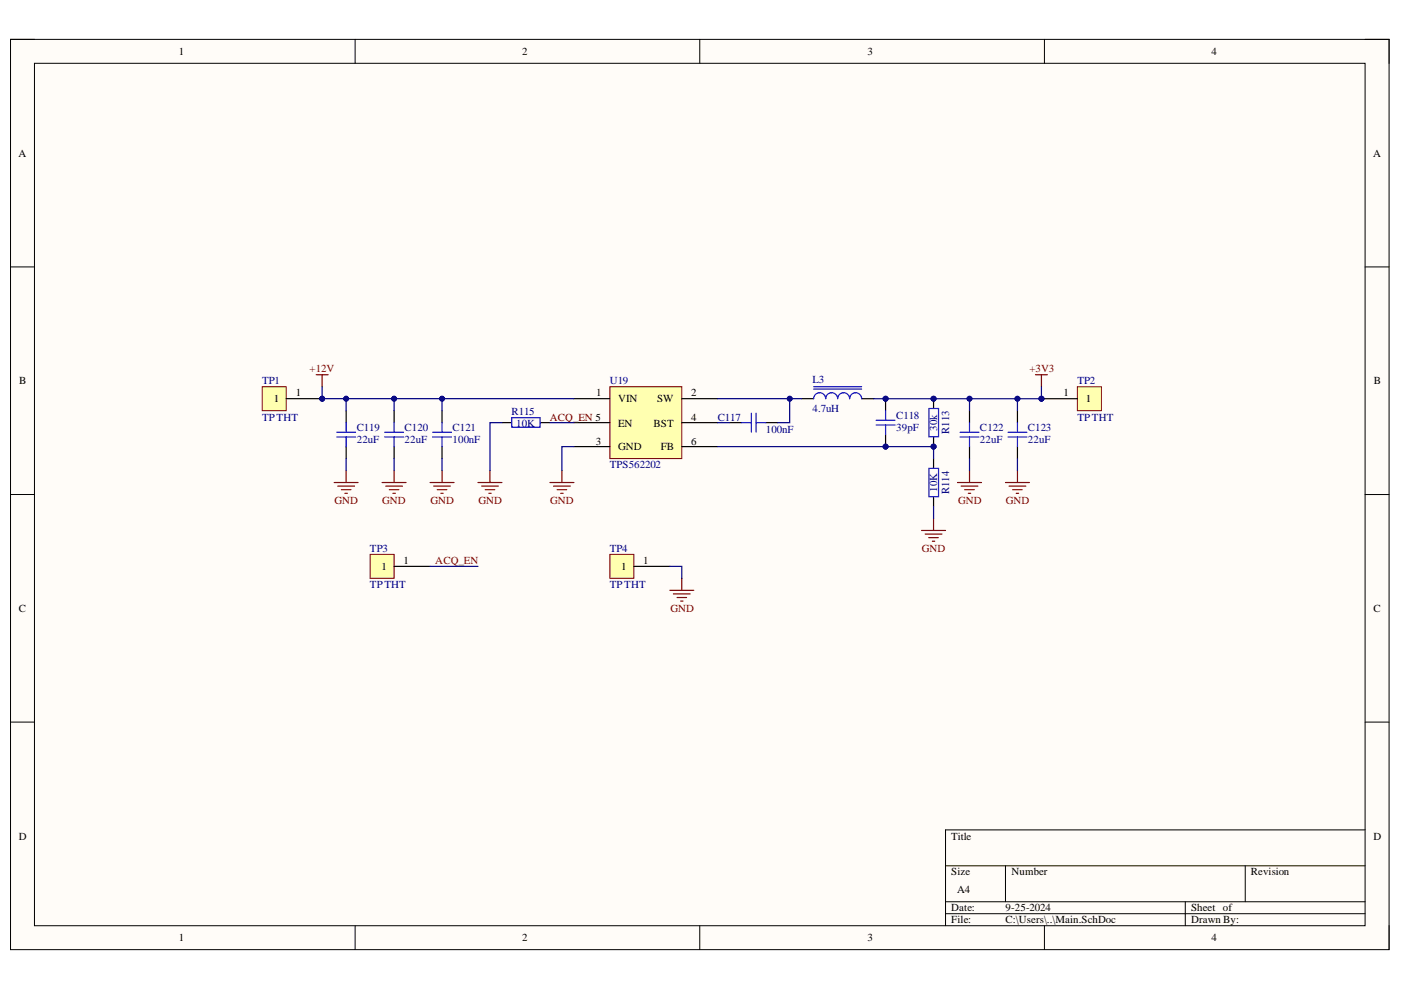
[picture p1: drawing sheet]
<svg xmlns="http://www.w3.org/2000/svg" width="297mm" height="210mm" viewBox="0 0 297 210" stroke-linecap="round" stroke-linejoin="round" font-family="sans-serif">
<defs><g id="words">
<g font-size="2.3">
<text x="37.9" y="11.7">1</text>
<text x="110.7" y="11.7">2</text>
<text x="183.9" y="11.7">3</text>
<text x="256.8" y="11.7">4</text>
<text x="3.9" y="33.3">A</text>
<text x="291.1" y="33.3">A</text>
<text x="4.1" y="81.5">B</text>
<text x="291.3" y="81.5">B</text>
<text x="58" y="85.3">1</text>
<text x="62.7" y="84">1</text>
<text x="126.4" y="84">1</text>
<text x="131" y="85.3">VIN</text>
<text x="139.3" y="85.3">SW</text>
<text x="146.5" y="84">2</text>
<text x="146.5" y="89.2">4</text>
<text x="225.5" y="84">1</text>
<text x="230.2" y="85.3">1</text>
<text x="126.3" y="94.2">3</text>
<text x="131" y="95.5">GND</text>
<text x="131" y="90.4">EN</text>
<text x="138.6" y="90.4">BST</text>
<text x="140.1" y="95.5">FB</text>
<text x="146.5" y="94.2">6</text>
<text x="85.5" y="119.6">1</text>
<text x="136.4" y="119.6">1</text>
<text x="80.9" y="120.9">1</text>
<text x="131.7" y="120.9">1</text>
<text x="4" y="129.7">C</text>
<text x="291.2" y="129.7">C</text>
<text x="4" y="178">D</text>
<text x="201.7" y="178">Title</text>
<text x="291.2" y="178">D</text>
<text x="201.7" y="185.6">Size</text>
<text x="214.5" y="185.6">Number</text>
<text x="265.2" y="185.6">Revision</text>
<text x="203" y="189.4">A4</text>
<text x="201.7" y="193.2">Date:</text>
<text x="201.7" y="195.8">File:</text>
<text x="213.2" y="193.2">9-25-2024</text>
<text x="213.2" y="195.8">C:\Users\..\Main.SchDoc</text>
<text x="252.5" y="193.2">Sheet of</text>
<text x="252.5" y="195.8">Drawn By:</text>
<text x="37.9" y="199.6">1</text>
<text x="110.7" y="199.6">2</text>
<text x="183.9" y="199.6">3</text>
<text x="256.8" y="199.6">4</text>
</g>
<g font-size="2.3" fill="#000080">
<text x="55.6" y="81.5">TP1</text>
<text x="129.3" y="81.5">U19</text>
<text x="172.2" y="81.2">L3</text>
<text x="228.4" y="81.5">TP2</text>
<text x="55.6" y="89.2">TPTHT</text>
<text x="108.5" y="88.1">R115</text>
<text x="152.2" y="89.2">C117</text>
<text x="172.2" y="87.3">4.7uH</text>
<text x="190" y="88.9">C118</text>
<text x="228.4" y="89.2">TPTHT</text>
<text x="75.6" y="91.5">C119</text>
<text x="75.6" y="94">22uF</text>
<text x="85.8" y="91.5">C120</text>
<text x="85.8" y="94">22uF</text>
<text x="95.9" y="91.5">C121</text>
<text x="95.9" y="94">100nF</text>
<text x="109.5" y="90.4">10K</text>
<text x="162.3" y="91.7">100nF</text>
<text x="190" y="91.5">39pF</text>
<text x="198.7" y="91.4" transform="rotate(-90 198.7 91.4)">30k</text>
<text x="201.3" y="92" transform="rotate(-90 201.3 92)">R113</text>
<text x="207.8" y="91.5">C122</text>
<text x="207.8" y="94">22uF</text>
<text x="217.9" y="91.5">C123</text>
<text x="217.9" y="94">22uF</text>
<text x="129.3" y="99.3">TPS562202</text>
<text x="198.7" y="104.3" transform="rotate(-90 198.7 104.3)">10K</text>
<text x="201.3" y="104.7" transform="rotate(-90 201.3 104.7)">R114</text>
<text x="78.4" y="117.1">TP3</text>
<text x="129.3" y="117.1">TP4</text>
<text x="78.4" y="124.7">TPTHT</text>
<text x="129.3" y="124.7">TPTHT</text>
</g>
<g font-size="2.3" fill="#800000">
<text x="65.6" y="78.9">+12V</text>
<text x="218.3" y="78.9">+3V3</text>
<text x="116.6" y="89.2">ACQ_EN 5</text>
<text x="70.9" y="106.9">GND</text>
<text x="81" y="106.9">GND</text>
<text x="91.3" y="106.9">GND</text>
<text x="101.4" y="106.9">GND</text>
<text x="116.7" y="106.9">GND</text>
<text x="203.1" y="106.9">GND</text>
<text x="213.3" y="106.9">GND</text>
<text x="92.3" y="119.6">ACQ_EN</text>
<text x="195.4" y="117.1">GND</text>
<text x="142.1" y="129.7">GND</text>
</g>
</g></defs>
<path d="M2.2 8.3h292.3v193h-292.3z" fill-rule="evenodd" fill="#fffcf8"/>
<path d="M2.2 8.3h292.3v193h-292.3z" fill="none" stroke="#000" stroke-width=".21"/>
<path d="M7.3 13.4h282.1v182.9h-282.1z" fill-rule="evenodd" fill="#fffcf8"/>
<g fill="none" stroke="#000" stroke-width=".21">
<path d="M2.2 8.3h5.1M7.3 13.4h282.1v182.9h-282.1zM75.3 8.3v5.1M148.4 8.3v5.1M221.4 8.3v5.1M289.4 8.3h5.1v5.1M2.2 56.6h5.1M289.4 56.6h5.1M2.2 104.8h5.1M289.4 104.9h5.1M2.2 153.1h5.1M289.4 153.1h5.1"/>
<path d="M289.4 176h-88.9v20.3M75.3 196.3v5M148.4 196.3v5M200.5 183.6h88.9M200.5 191.2h88.9M200.5 193.7h88.9M213.2 183.6v7.6M221.4 196.3v5M251.3 191.2v5.1M264 183.6v7.6M294.5 196.3v5"/>
</g>
<path d="M129.3 82h15.3v15.2h-15.3z" fill-rule="evenodd" fill="#ffffb0"/>
<path d="M129.3 82h15.3v15.2h-15.3z" fill="none" stroke="#800000" stroke-width=".21"/>
<path d="M93.7 87.1v2.5M93.7 94.7v2.5M121.7 84.5h7.6M121.7 94.7h7.6M121.7 89.6h7.6M144.6 84.5h7.6M144.6 94.7h7.6M144.6 89.6h7.6M154.7 89.6h2.6M162.3 89.6h2.6M197.9 97.2v2M197.9 105.4v2" fill="none" stroke="#000" stroke-width=".25"/>
<path d="M91.7 91.7h4M91.7 92.6h4M93.7 89.6v2.1M93.7 92.6v2.1M157.3 89.6h2M159.3 87.6v4M160.3 89.6h2M160.3 87.6v4M196.9 99.3h2.1v6h-2.1z" fill="none" stroke="#00f" stroke-width=".25"/>
<g fill="none" stroke="#800000" stroke-width=".25">
<path d="M93.7 99.8v2.5M119.1 99.8v2.5M91.2 102.3h5.1M91.9 103.1h3.6M92.7 103.8h2M93.5 104.6h.5M116.6 102.3h5.1M117.4 103.1h3.5M118.1 103.8h2.1M118.9 104.6h.5M195.4 112.5h5.1M196.2 113.2h3.5"/>
<path d="M196.9 114h2M197.7 114.8h.5M197.9 109.9v2.6"/>
</g>
<circle cx="187.8" cy="94.7" r=".51" fill="#000080"/>
<circle cx="187.8" cy="94.7" r=".51" fill="none" stroke="#000080" stroke-width=".21"/>
<circle cx="187.8" cy="84.5" r=".51" fill="#000080"/>
<circle cx="187.8" cy="84.5" r=".51" fill="none" stroke="#000080" stroke-width=".21"/>
<path d="M187.8 92.2v2.5" fill="none" stroke="#000" stroke-width=".25"/>
<circle cx="187.8" cy="94.7" r=".51" fill="#000080"/>
<circle cx="187.8" cy="94.7" r=".51" fill="none" stroke="#000080" stroke-width=".21"/>
<path d="M187.8 84.5v2.6" fill="none" stroke="#000" stroke-width=".25"/>
<circle cx="187.8" cy="84.5" r=".51" fill="#000080"/>
<circle cx="187.8" cy="84.5" r=".51" fill="none" stroke="#000080" stroke-width=".21"/>
<g fill="none" stroke="#00f" stroke-width=".25">
<path d="M71.4 92.6h4M71.4 91.7h4M73.4 89.6v2.1M73.4 92.6v2.1M81.6 92.6h4M81.6 91.7h4M83.6 89.6v2.1M83.6 92.6v2.1M185.8 90.1h4M185.8 89.1h4M187.8 87.1v2M187.8 90.1v2.1"/>
<path d="M203.6 92.6h4M203.6 91.7h4M205.6 89.6v2.1M205.6 92.6v2.1M213.7 92.6h4M213.7 91.7h4M215.7 89.6v2.1M215.7 92.6v2.1"/>
</g>
<path d="M73.4 87.1v2.5M73.4 94.7v2.5M83.6 87.1v2.5M83.6 94.7v2.5M205.6 87.1v2.5M205.6 94.7v2.5M215.7 87.1v2.5M215.7 94.7v2.5" fill="none" stroke="#000" stroke-width=".25"/>
<g fill="none" stroke="#800000" stroke-width=".25">
<path d="M67 79.5h2.6M68.3 79.5v2.5M219.5 79.5h2.6M220.8 79.5v2.5M73.4 99.8v2.5M83.6 99.8v2.5M205.6 99.8v2.5M215.7 99.8v2.5M70.8 102.3h5.1M71.6 103.1h3.6M72.4 103.8h2M73.1 104.6h.5"/>
<path d="M81 102.3h5.1M81.8 103.1h3.5M82.5 103.8h2.1M83.3 104.6h.5M203 102.3h5.1M203.8 103.1h3.5M204.5 103.8h2.1M205.3 104.6h.5M213.2 102.3h5.1M213.9 103.1h3.6M214.7 103.8h2M215.5 104.6h.5"/>
</g>
<circle cx="197.9" cy="84.5" r=".51" fill="#000080"/>
<circle cx="197.9" cy="84.5" r=".51" fill="none" stroke="#000080" stroke-width=".21"/>
<circle cx="197.9" cy="94.7" r=".51" fill="#000080"/>
<circle cx="197.9" cy="94.7" r=".51" fill="none" stroke="#000080" stroke-width=".21"/>
<path d="M197.9 84.5v2" fill="none" stroke="#000" stroke-width=".25"/>
<circle cx="197.9" cy="84.5" r=".51" fill="#000080"/>
<circle cx="197.9" cy="84.5" r=".51" fill="none" stroke="#000080" stroke-width=".21"/>
<path d="M197.9 92.7v2" fill="none" stroke="#000" stroke-width=".25"/>
<circle cx="197.9" cy="94.7" r=".51" fill="#000080"/>
<circle cx="197.9" cy="94.7" r=".51" fill="none" stroke="#000080" stroke-width=".21"/>
<path d="M108.5 88.6h6v2h-6zM172.5 84.5a1.27 1.27 0 0 1 1.3-1.2 1.27 1.27 0 0 1 1.3 1.2 1.27 1.27 0 0 1 1.2-1.2 1.27 1.27 0 0 1 1.3 1.2 1.27 1.27 0 0 1 1.3-1.2 1.27 1.27 0 0 1 1.2 1.2 1.27 1.27 0 0 1 1.3-1.2 1.27 1.27 0 0 1 1.3 1.2M172.5 82.5h10.2M172.5 82h10.2M196.9 86.6h2.1v6h-2.1z" fill="none" stroke="#00f" stroke-width=".25"/>
<path d="M106.4 89.6h2M114.6 89.6h2M170 84.5h2.5M182.7 84.5h2.5" fill="none" stroke="#000" stroke-width=".25"/>
<path d="M103.9 99.8v2.5M101.3 102.3h5.1M102.1 103.1h3.6M102.9 103.8h2M103.6 104.6h.5" fill="none" stroke="#800000" stroke-width=".25"/>
<circle cx="68.3" cy="84.5" r=".51" fill="#000080"/>
<circle cx="68.3" cy="84.5" r=".51" fill="none" stroke="#000080" stroke-width=".21"/>
<path d="M55.6 82h5.1v5.1h-5.1z" fill-rule="evenodd" fill="#ffffb0"/>
<path d="M55.6 82h5.1v5.1h-5.1z" fill="none" stroke="#800000" stroke-width=".21"/>
<path d="M60.7 84.5h7.6" fill="none" stroke="#000" stroke-width=".25"/>
<circle cx="68.3" cy="84.5" r=".51" fill="#000080"/>
<circle cx="68.3" cy="84.5" r=".51" fill="none" stroke="#000080" stroke-width=".21"/>
<circle cx="220.8" cy="84.5" r=".51" fill="#000080"/>
<circle cx="220.8" cy="84.5" r=".51" fill="none" stroke="#000080" stroke-width=".21"/>
<path d="M228.4 82h5.1v5.1h-5.1z" fill-rule="evenodd" fill="#ffffb0"/>
<path d="M228.4 82h5.1v5.1h-5.1z" fill="none" stroke="#800000" stroke-width=".21"/>
<path d="M220.8 84.5h7.6" fill="none" stroke="#000" stroke-width=".25"/>
<circle cx="220.8" cy="84.5" r=".51" fill="#000080"/>
<circle cx="220.8" cy="84.5" r=".51" fill="none" stroke="#000080" stroke-width=".21"/>
<path d="M78.5 117.5h5.1v5.1h-5.1z" fill-rule="evenodd" fill="#ffffb0"/>
<path d="M78.5 117.5h5.1v5.1h-5.1z" fill="none" stroke="#800000" stroke-width=".21"/>
<path d="M83.6 120.1h7.6" fill="none" stroke="#000" stroke-width=".25"/>
<path d="M152.2 84.5h15.2v5.1h-2.5M152.2 89.6h2.5" fill="none" stroke="#000080" stroke-width=".25"/>
<circle cx="167.4" cy="84.5" r=".51" fill="#000080"/>
<circle cx="167.4" cy="84.5" r=".51" fill="none" stroke="#000080" stroke-width=".21"/>
<path d="M152.2 94.7h45.7v2.5M197.9 107.4v2.5" fill="none" stroke="#000080" stroke-width=".25"/>
<circle cx="197.9" cy="94.7" r=".51" fill="#000080"/>
<circle cx="197.9" cy="94.7" r=".51" fill="none" stroke="#000080" stroke-width=".21"/>
<circle cx="187.8" cy="94.7" r=".51" fill="#000080"/>
<circle cx="187.8" cy="94.7" r=".51" fill="none" stroke="#000080" stroke-width=".21"/>
<path d="M73.4 97.2v2.6M83.6 97.2v2.6M93.7 97.2v2.6M121.7 94.7h-2.6v5.1M167.4 84.5h2.6M205.6 97.2v2.6M215.7 97.2v2.6" fill="none" stroke="#000080" stroke-width=".25"/>
<circle cx="167.4" cy="84.5" r=".51" fill="#000080"/>
<circle cx="167.4" cy="84.5" r=".51" fill="none" stroke="#000080" stroke-width=".21"/>
<path d="M93.7 84.5v2.6" fill="none" stroke="#000080" stroke-width=".25"/>
<circle cx="93.7" cy="84.5" r=".51" fill="#000080"/>
<circle cx="93.7" cy="84.5" r=".51" fill="none" stroke="#000080" stroke-width=".21"/>
<path d="M83.6 84.5v2.6" fill="none" stroke="#000080" stroke-width=".25"/>
<circle cx="83.6" cy="84.5" r=".51" fill="#000080"/>
<circle cx="83.6" cy="84.5" r=".51" fill="none" stroke="#000080" stroke-width=".21"/>
<path d="M73.4 84.5v2.6" fill="none" stroke="#000080" stroke-width=".25"/>
<circle cx="73.4" cy="84.5" r=".51" fill="#000080"/>
<circle cx="73.4" cy="84.5" r=".51" fill="none" stroke="#000080" stroke-width=".21"/>
<path d="M205.6 84.5v2.6" fill="none" stroke="#000080" stroke-width=".25"/>
<circle cx="205.6" cy="84.5" r=".51" fill="#000080"/>
<circle cx="205.6" cy="84.5" r=".51" fill="none" stroke="#000080" stroke-width=".21"/>
<path d="M215.7 84.5v2.6" fill="none" stroke="#000080" stroke-width=".25"/>
<circle cx="215.7" cy="84.5" r=".51" fill="#000080"/>
<circle cx="215.7" cy="84.5" r=".51" fill="none" stroke="#000080" stroke-width=".21"/>
<path d="M68.3 82v2.5h53.4M116.6 89.6h5.1" fill="none" stroke="#000080" stroke-width=".25"/>
<circle cx="93.7" cy="84.5" r=".51" fill="#000080"/>
<circle cx="93.7" cy="84.5" r=".51" fill="none" stroke="#000080" stroke-width=".21"/>
<circle cx="83.6" cy="84.5" r=".51" fill="#000080"/>
<circle cx="83.6" cy="84.5" r=".51" fill="none" stroke="#000080" stroke-width=".21"/>
<circle cx="73.4" cy="84.5" r=".51" fill="#000080"/>
<circle cx="73.4" cy="84.5" r=".51" fill="none" stroke="#000080" stroke-width=".21"/>
<circle cx="68.3" cy="84.5" r=".51" fill="#000080"/>
<circle cx="68.3" cy="84.5" r=".51" fill="none" stroke="#000080" stroke-width=".21"/>
<path d="M106.4 89.6h-2.5v10.2M220.8 82v2.5h-35.6" fill="none" stroke="#000080" stroke-width=".25"/>
<circle cx="187.8" cy="84.5" r=".51" fill="#000080"/>
<circle cx="187.8" cy="84.5" r=".51" fill="none" stroke="#000080" stroke-width=".21"/>
<circle cx="197.9" cy="84.5" r=".51" fill="#000080"/>
<circle cx="197.9" cy="84.5" r=".51" fill="none" stroke="#000080" stroke-width=".21"/>
<circle cx="205.6" cy="84.5" r=".51" fill="#000080"/>
<circle cx="205.6" cy="84.5" r=".51" fill="none" stroke="#000080" stroke-width=".21"/>
<circle cx="215.7" cy="84.5" r=".51" fill="#000080"/>
<circle cx="215.7" cy="84.5" r=".51" fill="none" stroke="#000080" stroke-width=".21"/>
<circle cx="220.8" cy="84.5" r=".51" fill="#000080"/>
<circle cx="220.8" cy="84.5" r=".51" fill="none" stroke="#000080" stroke-width=".21"/>
<path d="M91.2 120.1h10.1" fill="none" stroke="#000080" stroke-width=".25"/>
<path d="M129.3 117.5h5.1v5.1h-5.1z" fill-rule="evenodd" fill="#ffffb0"/>
<path d="M129.3 117.5h5.1v5.1h-5.1z" fill="none" stroke="#800000" stroke-width=".21"/>
<path d="M134.4 120.1h7.6" fill="none" stroke="#000" stroke-width=".25"/>
<path d="M142 125.2h5.1M142.8 125.9h3.5M143.5 126.7h2.1M144.3 127.5h.5M144.6 122.6v2.6" fill="none" stroke="#800000" stroke-width=".25"/>
<path d="M142 120.1h2.6v2.5" fill="none" stroke="#000080" stroke-width=".25"/>
<use href="#words"/>
</svg>
